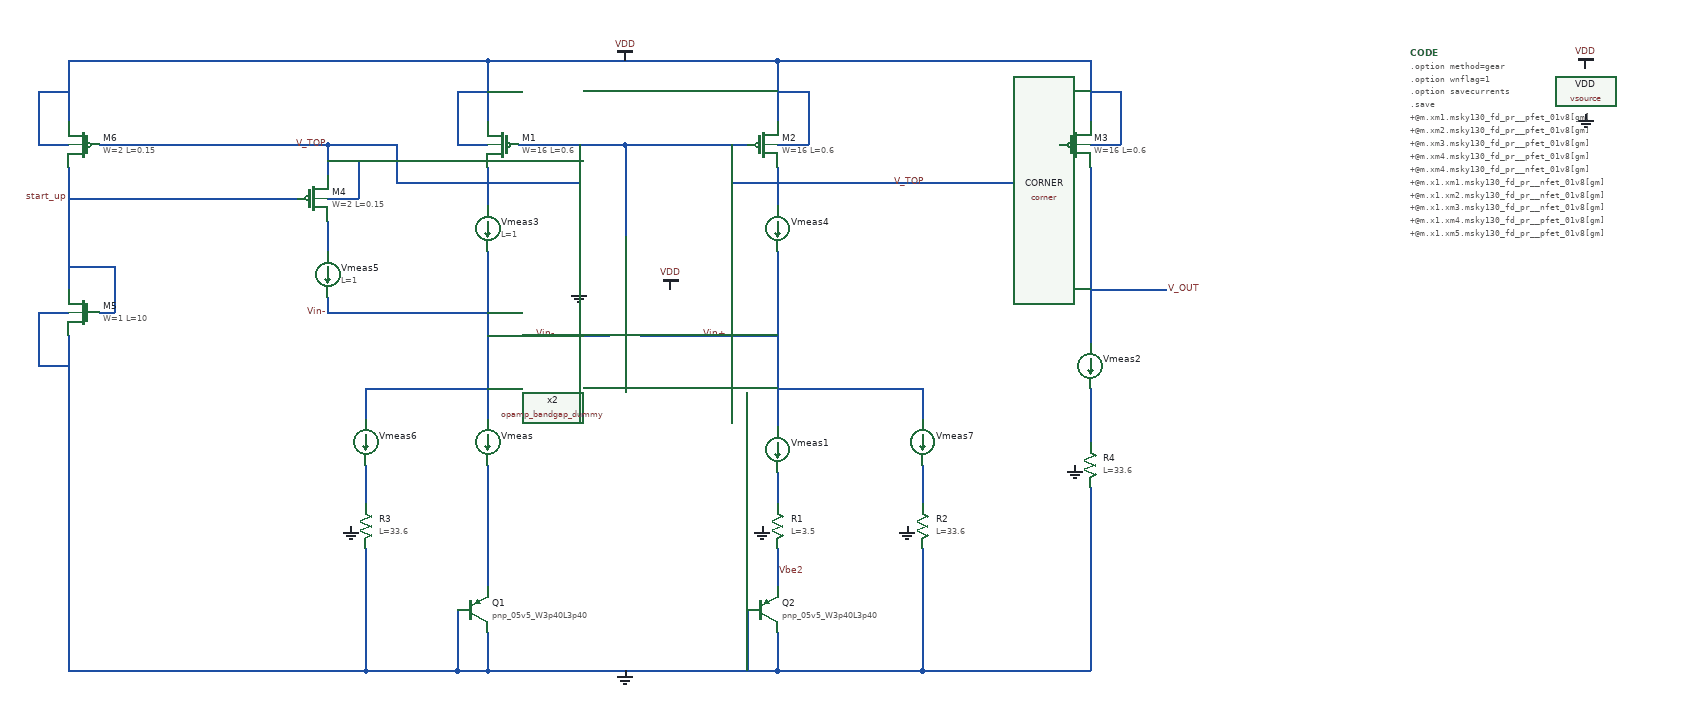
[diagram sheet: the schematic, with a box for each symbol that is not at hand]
v {xschem version=3.4.6 file_version=1.2}
G {}
K {}
V {}
S {}
E {}
B 2 1490 -1230 2100 -680 {flags=graph

y2=1.3
ypos1=0
ypos2=2
divy=5
subdivy=4
unity=1
x1=0.27242027
x2=3.9588202
divx=5
subdivx=4
xlabmag=1.0
ylabmag=1.0


dataset=-1
unitx=1
logx=0
logy=0











linewidth_mult=4
























y1=-9e-277


color=5
node=v_out}
B 2 760 -1660 990 -1500 {flags=graph

y2=0.00028
ypos1=0
ypos2=2
divy=5
subdivy=4
unity=1
x1=0.27242027
x2=3.9588202
divx=5
subdivx=4
xlabmag=1.0
ylabmag=1.0


dataset=-1
unitx=1
logx=0
logy=0











linewidth_mult=1
























y1=-3.2e-05



color=12
node=i(vmeas5)}
B 2 1490 -640 2100 -90 {flags=graph

y2=2.9e-08
ypos1=0
ypos2=2
divy=5
subdivy=4
unity=1
x1=0.27242027
x2=3.9588202
divx=5
subdivx=4
xlabmag=1.0
ylabmag=1.0


dataset=-1
unitx=1
logx=0
logy=0











linewidth_mult=4
























y1=0




color=6
node=i(@m.xm4.msky130_fd_pr__pfet_01v8[id])}
B 2 460 -1660 690 -1500 {flags=graph

y2=0.85
ypos1=0
ypos2=2
divy=5
subdivy=4
unity=1
x1=0.27242027
x2=3.9588202
divx=5
subdivx=4
xlabmag=1.0
ylabmag=1.0


dataset=-1
unitx=1
logx=0
logy=0











linewidth_mult=1
























y1=2.5e-16


color="6 7"
node="v_top
vin-"}
B 2 0 -1250 230 -1070 {flags=graph

y2=1.8
ypos1=0
ypos2=2
divy=5
subdivy=4
unity=1
x1=0.27242027
x2=3.9588202
divx=5
subdivx=4
xlabmag=1.0
ylabmag=1.0


dataset=-1
unitx=1
logx=0
logy=0











linewidth_mult=1
























y1=-0.61



node="v_out
start_up
vdd
vin-
v_top"
color="7 6 12 18 11"}
B 2 -400 -1270 -170 -1060 {flags=graph

y2=0.00028
ypos1=0
ypos2=2
divy=5
subdivy=4
unity=1
x1=0.27242027
x2=3.9588202
divx=5
subdivx=4
xlabmag=1.0
ylabmag=1.0


dataset=-1
unitx=1
logx=0
logy=0











linewidth_mult=1
























y1=6.5e-17



color=6
node=i(@m.xm4.msky130_fd_pr__pfet_01v8[id])}
N 480 -650 860 -650 {
lab=GND}
N 440 -730 440 -650 {
lab=GND}
N 820 -730 820 -650 {
lab=GND}
N 440 -650 480 -650 {
lab=GND}
N 520 -1340 660 -1340 {
lab=V_TOP}
N 660 -1340 820 -1340 {
lab=V_TOP}
N 480 -1450 480 -1370 {
lab=VDD}
N 480 -1450 860 -1450 {
lab=VDD}
N 860 -1450 860 -1370 {
lab=VDD}
N 860 -1450 1270 -1450 {
lab=VDD}
N 320 -1020 480 -1020 {
lab=Vin-}
N 860 -810 860 -760 {lab=Vbe2}
N 1050 -810 1050 -650 {lab=GND}
N 320 -810 320 -650 {lab=GND}
N 860 -1020 1050 -1020 {lab=Vin+}
N 860 -650 1050 -650 {lab=GND}
N 1270 -890 1270 -650 {lab=GND}
N 1050 -650 1270 -650 {lab=GND}
N 860 -1340 900 -1340 {lab=VDD}
N 900 -1410 900 -1340 {lab=VDD}
N 860 -1410 900 -1410 {lab=VDD}
N 440 -1340 480 -1340 {lab=VDD}
N 440 -1410 440 -1340 {lab=VDD}
N 440 -1410 480 -1410 {lab=VDD}
N 1270 -1450 1270 -1370 {
lab=VDD}
N 1270 -1340 1310 -1340 {lab=VDD}
N 1310 -1410 1310 -1340 {lab=VDD}
N 1270 -1410 1310 -1410 {lab=VDD}
N 800 -1340 800 -1290 {lab=V_TOP}
N 800 -1290 1210 -1290 {lab=V_TOP}
N 1210 -1340 1210 -1290 {lab=V_TOP}
N 1210 -1340 1230 -1340 {lab=V_TOP}
N 1270 -1150 1370 -1150 {lab=V_OUT}
N 680 -1090 860 -1090 {lab=Vin+}
N 480 -1090 640 -1090 {lab=Vin-}
N 320 -650 440 -650 {lab=GND}
N 860 -700 860 -650 {lab=GND}
N 480 -700 480 -650 {lab=GND}
N 860 -910 860 -870 {lab=#net1}
N 480 -920 480 -760 {lab=#net2}
N 1270 -1020 1270 -950 {lab=#net3}
N 1270 -1310 1270 -1080 {lab=V_OUT}
N 860 -1310 860 -1260 {lab=#net4}
N 480 -1310 480 -1260 {lab=#net5}
N 270 -1340 270 -1300 {lab=V_TOP}
N -70 -1240 -70 -1150 {lab=start_up}
N -70 -1450 -70 -1370 {
lab=VDD}
N -110 -1340 -70 -1340 {lab=VDD}
N -110 -1410 -110 -1340 {lab=VDD}
N -110 -1410 -70 -1410 {lab=VDD}
N -70 -1310 -70 -1240 {lab=start_up}
N -70 -1450 480 -1450 {lab=VDD}
N 270 -1340 360 -1340 {lab=V_TOP}
N 360 -1340 360 -1290 {lab=V_TOP}
N 360 -1290 600 -1290 {lab=V_TOP}
N -70 -1270 230 -1270 {lab=start_up}
N -70 -650 320 -650 {lab=GND}
N 660 -1340 660 -1220 {lab=V_TOP}
N 480 -1200 480 -980 {lab=Vin-}
N 860 -1200 860 -970 {lab=Vin+}
N 600 -1340 600 -1290 {lab=V_TOP}
N 270 -1120 480 -1120 {lab=Vin-}
N -110 -1050 -70 -1050 {lab=GND}
N -110 -1120 -110 -1050 {lab=GND}
N -110 -1120 -70 -1120 {lab=GND}
N -70 -1090 -70 -1020 {lab=GND}
N -70 -730 -70 -650 {lab=GND}
N 270 -1320 310 -1320 {lab=V_TOP}
N 270 -1270 310 -1270 {lab=V_TOP}
N 310 -1320 310 -1270 {lab=V_TOP}
N 270 -1140 270 -1120 {lab=Vin-}
N 270 -1240 270 -1200 {lab=#net6}
N -70 -1020 -70 -730 {lab=GND}
N 1050 -920 1050 -870 {lab=#net7}
N 1050 -1020 1050 -980 {lab=Vin+}
N 320 -1020 320 -980 {lab=Vin-}
N 320 -920 320 -870 {lab=#net8}
N -30 -1340 270 -1340 {lab=V_TOP}
N -70 -1180 -10 -1180 {lab=start_up}
N -10 -1180 -10 -1120 {lab=start_up}
N -30 -1120 -10 -1120 {lab=start_up}
C {devices/vsource.sym} 1920 -1410 0 0 {name=VDD value=1.8 savecurrent=false
* "pwl(0 0 1us 0 2us 1.8)"}
C {devices/gnd.sym} 1920 -1380 0 0 {name=l3 lab=GND}
C {devices/vdd.sym} 1920 -1440 0 0 {name=l4 lab=VDD}
C {sky130_fd_pr/corner.sym} 1480 -1460 0 0 {name=CORNER only_toplevel=false corner=tt}
C {devices/code.sym} 1690 -1460 0 0 {name=CODE only_toplevel=false value="

.option method=gear
.option wnflag=1
.option savecurrents

.save
+@m.xm1.msky130_fd_pr__pfet_01v8[gm]
+@m.xm2.msky130_fd_pr__pfet_01v8[gm]
+@m.xm3.msky130_fd_pr__pfet_01v8[gm]
+@m.xm4.msky130_fd_pr__pfet_01v8[gm]
+@m.xm4.msky130_fd_pr__nfet_01v8[gm]
+@m.x1.xm1.msky130_fd_pr__nfet_01v8[gm]
+@m.x1.xm2.msky130_fd_pr__nfet_01v8[gm]
+@m.x1.xm3.msky130_fd_pr__nfet_01v8[gm]
+@m.x1.xm4.msky130_fd_pr__pfet_01v8[gm]
+@m.x1.xm5.msky130_fd_pr__pfet_01v8[gm]
+@m.x1.xm6.msky130_fd_pr__nfet_01v8[gm]
+@m.x1.xm7.msky130_fd_pr__pfet_01v8[gm]
+@m.x2.xm1.msky130_fd_pr__nfet_01v8[gm]
+@m.x2.xm2.msky130_fd_pr__nfet_01v8[gm]
+@m.x2.xm3.msky130_fd_pr__nfet_01v8[gm]
+@m.x2.xm4.msky130_fd_pr__pfet_01v8[gm]
+@m.x2.xm5.msky130_fd_pr__pfet_01v8[gm]
+@m.x2.xm6.msky130_fd_pr__pfet_01v8[gm]
+@m.x2.xm7.msky130_fd_pr__pfet_01v8[gm]

* .ic v(vin-) = 0.8
.ic v(v_top) = 1.8

.control
  save all
  * dc temp -40 120 10 VDD 0 4.0 0.2
  dc VDD 0 4.0 0.2 temp -40 120 40
  * dc VDD 0 4.0 0.2
  * tran 1ns 10us
  remzerovec
  write tb_low_voltage_BGR_4.raw
  set appendwrite
.endc


"}
C {devices/gnd.sym} 660 -650 0 0 {name=l1 lab=GND}
C {devices/vdd.sym} 720 -1150 1 0 {name=l5 lab=VDD}
C {devices/gnd.sym} 600 -1150 1 0 {name=l8 lab=GND
W=4}
C {devices/lab_pin.sym} 860 -780 2 0 {name=p5 sig_type=std_logic lab=Vbe2}
C {devices/vdd.sym} 660 -1450 0 0 {name=l2 lab=VDD}
C {devices/lab_pin.sym} 1370 -1150 2 0 {name=p4 sig_type=std_logic lab=V_OUT
}
C {sky130_fd_pr/pnp_05v5.sym} 460 -730 0 0 {name=Q1
model=pnp_05v5_W3p40L3p40
m=1
spiceprefix=X
}
C {sky130_fd_pr/pnp_05v5.sym} 840 -730 0 0 {name=Q2
model=pnp_05v5_W3p40L3p40
m=6
spiceprefix=X
}
C {devices/gnd.sym} 840 -840 1 0 {name=l6 lab=GND}
C {devices/gnd.sym} 1030 -840 1 0 {name=l7 lab=GND}
C {devices/gnd.sym} 1250 -920 1 0 {name=l9 lab=GND}
C {sky130_fd_pr/pfet_01v8.sym} 500 -1340 0 1 {name=M1
W=16
L=0.6
nf=4
mult=1
ad="'int((nf+1)/2) * W/nf * 0.29'" 
pd="'2*int((nf+1)/2) * (W/nf + 0.29)'"
as="'int((nf+2)/2) * W/nf * 0.29'" 
ps="'2*int((nf+2)/2) * (W/nf + 0.29)'"
nrd="'0.29 / W'" nrs="'0.29 / W'"
sa=0 sb=0 sd=0
model=pfet_01v8
spiceprefix=X
}
C {sky130_fd_pr/pfet_01v8.sym} 840 -1340 0 0 {name=M2
W=16
L=0.6
nf=4
mult=1
ad="'int((nf+1)/2) * W/nf * 0.29'" 
pd="'2*int((nf+1)/2) * (W/nf + 0.29)'"
as="'int((nf+2)/2) * W/nf * 0.29'" 
ps="'2*int((nf+2)/2) * (W/nf + 0.29)'"
nrd="'0.29 / W'" nrs="'0.29 / W'"
sa=0 sb=0 sd=0
model=pfet_01v8
spiceprefix=X
}
C {sky130_fd_pr/pfet_01v8.sym} 1250 -1340 0 0 {name=M3
W=16
L=0.6
nf=4
mult=1
ad="'int((nf+1)/2) * W/nf * 0.29'" 
pd="'2*int((nf+1)/2) * (W/nf + 0.29)'"
as="'int((nf+2)/2) * W/nf * 0.29'" 
ps="'2*int((nf+2)/2) * (W/nf + 0.29)'"
nrd="'0.29 / W'" nrs="'0.29 / W'"
sa=0 sb=0 sd=0
model=pfet_01v8
spiceprefix=X
}
C {devices/gnd.sym} 300 -840 1 0 {name=l10 lab=GND}
C {lab_wire.sym} 1010 -1290 2 0 {name=p2 sig_type=std_logic lab=V_TOP}
C {lab_wire.sym} 760 -1090 2 0 {name=p6 sig_type=std_logic lab=Vin+}
C {lab_wire.sym} 570 -1090 2 1 {name=p1 sig_type=std_logic lab=Vin-}
C {ammeter.sym} 480 -950 0 0 {name=Vmeas savecurrent=true spice_ignore=0}
C {ammeter.sym} 860 -940 0 0 {name=Vmeas1 savecurrent=true spice_ignore=0}
C {ammeter.sym} 1270 -1050 0 0 {name=Vmeas2 savecurrent=true spice_ignore=0}
C {sky130_fd_pr/res_xhigh_po_0p35.sym} 860 -840 0 0 {name=R1
L=3.5
model=res_xhigh_po_0p35
spiceprefix=X
mult=1}
C {sky130_fd_pr/res_xhigh_po_0p35.sym} 1050 -840 0 0 {name=R2
L=33.6
model=res_xhigh_po_0p35
spiceprefix=X
mult=1}
C {sky130_fd_pr/res_xhigh_po_0p35.sym} 320 -840 0 0 {name=R3
L=33.6
model=res_xhigh_po_0p35
spiceprefix=X
mult=1}
C {sky130_fd_pr/res_xhigh_po_0p35.sym} 1270 -920 0 0 {name=R4
L=33.6
model=res_xhigh_po_0p35
spiceprefix=X
mult=1}
C {ammeter.sym} 480 -1230 0 0 {name=Vmeas3 savecurrent=true spice_ignore=0
L=1}
C {ammeter.sym} 860 -1230 0 0 {name=Vmeas4 savecurrent=true spice_ignore=0}
C {sky130_fd_pr/nfet_01v8.sym} -50 -1120 0 1 {name=M5
W=1
L=10
nf=1 
mult=1
ad="'int((nf+1)/2) * W/nf * 0.29'" 
pd="'2*int((nf+1)/2) * (W/nf + 0.29)'"
as="'int((nf+2)/2) * W/nf * 0.29'" 
ps="'2*int((nf+2)/2) * (W/nf + 0.29)'"
nrd="'0.29 / W'" nrs="'0.29 / W'"
sa=0 sb=0 sd=0
model=nfet_01v8
spiceprefix=X
}
C {sky130_fd_pr/pfet_01v8.sym} -50 -1340 0 1 {name=M6
W=2
L=0.15
nf=1
mult=1
ad="'int((nf+1)/2) * W/nf * 0.29'" 
pd="'2*int((nf+1)/2) * (W/nf + 0.29)'"
as="'int((nf+2)/2) * W/nf * 0.29'" 
ps="'2*int((nf+2)/2) * (W/nf + 0.29)'"
nrd="'0.29 / W'" nrs="'0.29 / W'"
sa=0 sb=0 sd=0
model=pfet_01v8
spiceprefix=X
}
C {devices/lab_pin.sym} -70 -1270 2 1 {name=p7 sig_type=std_logic lab=start_up}
C {lab_wire.sym} 270 -1120 2 1 {name=p3 sig_type=std_logic lab=Vin-}
C {lab_wire.sym} 270 -1340 0 0 {name=p8 sig_type=std_logic lab=V_TOP}
C {ammeter.sym} 270 -1170 0 0 {name=Vmeas5 savecurrent=true spice_ignore=0
L=1}
C {sky130_fd_pr/pfet_01v8.sym} 250 -1270 0 0 {name=M4
W=2
L=0.15
nf=1
mult=1
ad="'int((nf+1)/2) * W/nf * 0.29'" 
pd="'2*int((nf+1)/2) * (W/nf + 0.29)'"
as="'int((nf+2)/2) * W/nf * 0.29'" 
ps="'2*int((nf+2)/2) * (W/nf + 0.29)'"
nrd="'0.29 / W'" nrs="'0.29 / W'"
sa=0 sb=0 sd=0
model=pfet_01v8
spiceprefix=X
}
C {ammeter.sym} 320 -950 0 0 {name=Vmeas6 savecurrent=true spice_ignore=0}
C {ammeter.sym} 1050 -950 0 0 {name=Vmeas7 savecurrent=true spice_ignore=0}
C {opamp_bandgap_dummy.sym} 660 -1150 1 1 {name=x2}
